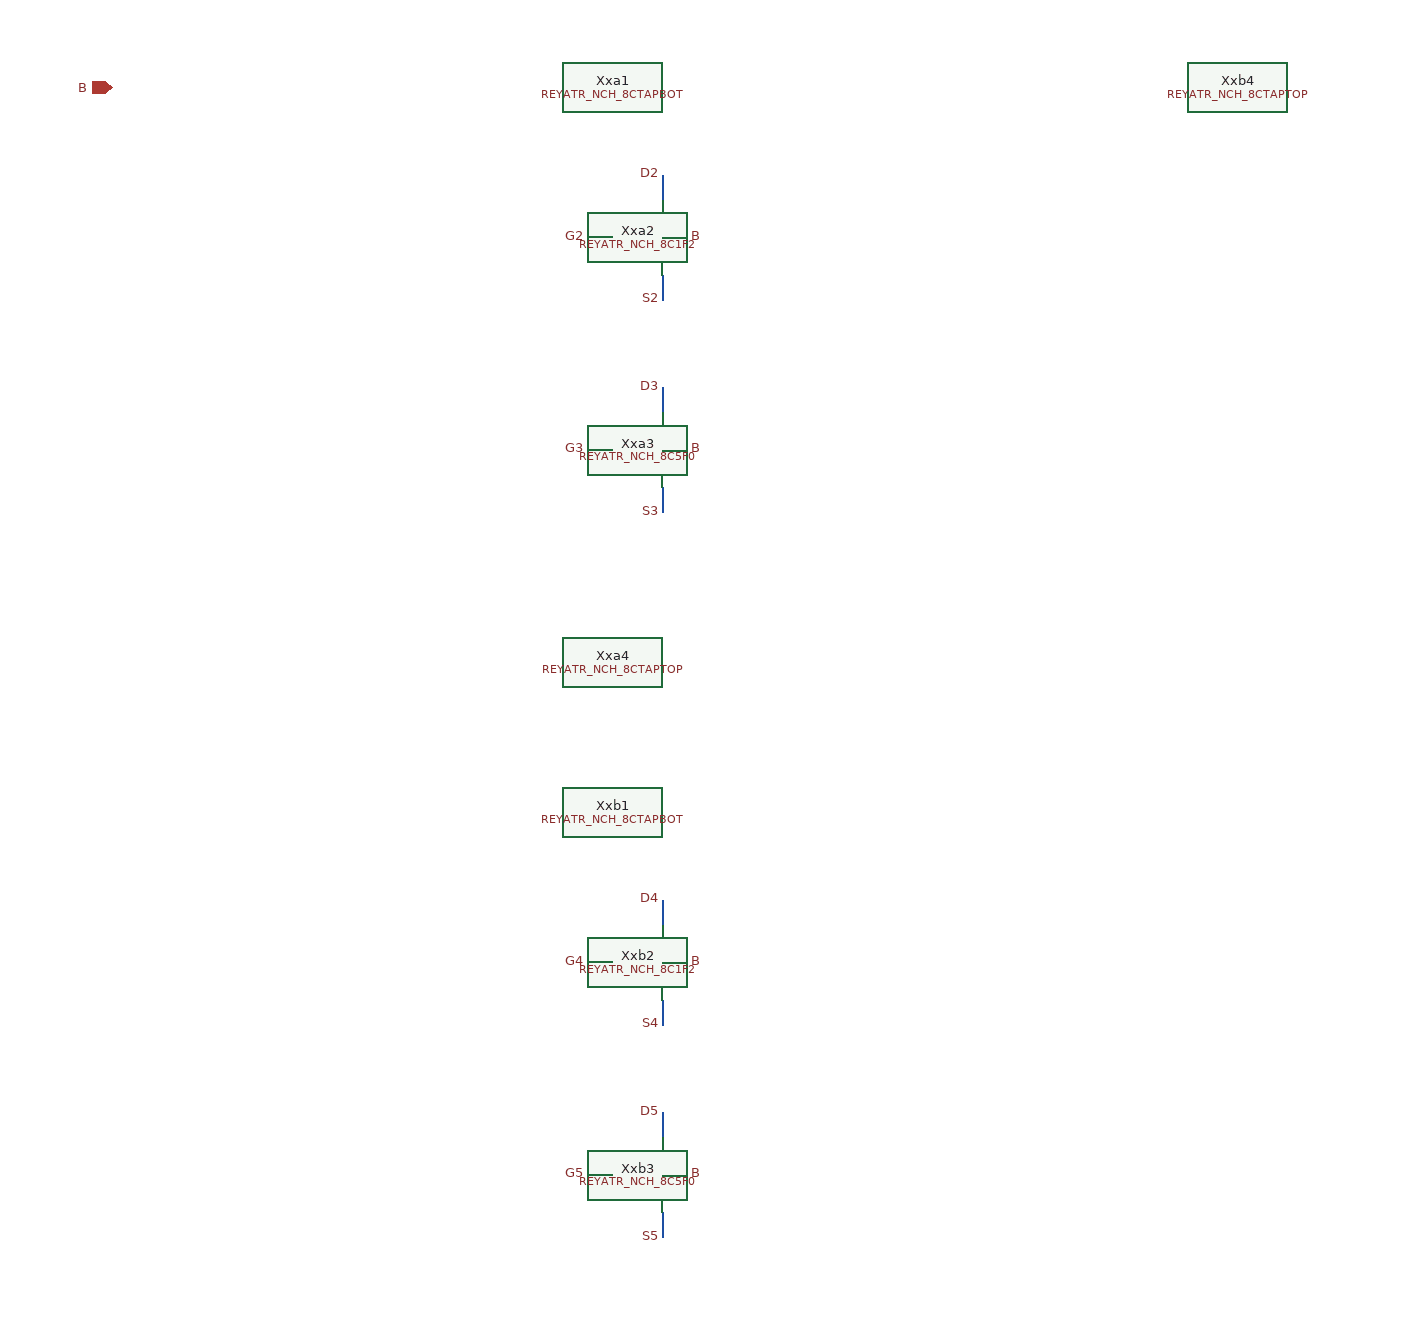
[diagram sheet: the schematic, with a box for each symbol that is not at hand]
v {xschem version=3.0.0 file_version=1.2 }
G {}
K {}
V {}
S {}
E {}
C {devices/iopin.sym} 0 0 0 0 {name=p0 lab=B}
C {LELO_TEMP_SKY130A/REYATR_NCH_8CTAPBOT.sym} 400 0 0 0 {name=Xxa1}
C {LELO_TEMP_SKY130A/REYATR_NCH_8C1F2.sym} 400 120.0 0 0 {name=Xxa2}
N 440.0 70.0 440.0 90.0 {lab=D2}
C {devices/lab_pin.sym} 440.0 70.0 3 0 {name=l0 sig_type=std_logic lab=D2 }
N 380.0 120.0 400.0 120.0 {lab=G2}
C {devices/lab_pin.sym} 380.0 120.0 0 0 {name=l1 sig_type=std_logic lab=G2 }
N 440.0 170.0 440.0 150.0 {lab=S2}
C {devices/lab_pin.sym} 440.0 170.0 1 0 {name=l2 sig_type=std_logic lab=S2 }
N 460.0 120.0 440.0 120.0 {lab=B}
C {devices/lab_pin.sym} 460.0 120.0 2 0 {name=l3 sig_type=std_logic lab=B }
C {LELO_TEMP_SKY130A/REYATR_NCH_8C5F0.sym} 400 290.0 0 0 {name=Xxa3}
N 440.0 240.0 440.0 260.0 {lab=D3}
C {devices/lab_pin.sym} 440.0 240.0 3 0 {name=l4 sig_type=std_logic lab=D3 }
N 380.0 290.0 400.0 290.0 {lab=G3}
C {devices/lab_pin.sym} 380.0 290.0 0 0 {name=l5 sig_type=std_logic lab=G3 }
N 440.0 340.0 440.0 320.0 {lab=S3}
C {devices/lab_pin.sym} 440.0 340.0 1 0 {name=l6 sig_type=std_logic lab=S3 }
N 460.0 290.0 440.0 290.0 {lab=B}
C {devices/lab_pin.sym} 460.0 290.0 2 0 {name=l7 sig_type=std_logic lab=B }
C {LELO_TEMP_SKY130A/REYATR_NCH_8CTAPTOP.sym} 400 460.0 0 0 {name=Xxa4}
C {LELO_TEMP_SKY130A/REYATR_NCH_8CTAPBOT.sym} 400 580.0 0 0 {name=Xxb1}
C {LELO_TEMP_SKY130A/REYATR_NCH_8C1F2.sym} 400 700.0 0 0 {name=Xxb2}
N 440.0 650.0 440.0 670.0 {lab=D4}
C {devices/lab_pin.sym} 440.0 650.0 3 0 {name=l8 sig_type=std_logic lab=D4 }
N 380.0 700.0 400.0 700.0 {lab=G4}
C {devices/lab_pin.sym} 380.0 700.0 0 0 {name=l9 sig_type=std_logic lab=G4 }
N 440.0 750.0 440.0 730.0 {lab=S4}
C {devices/lab_pin.sym} 440.0 750.0 1 0 {name=l10 sig_type=std_logic lab=S4 }
N 460.0 700.0 440.0 700.0 {lab=B}
C {devices/lab_pin.sym} 460.0 700.0 2 0 {name=l11 sig_type=std_logic lab=B }
C {LELO_TEMP_SKY130A/REYATR_NCH_8C5F0.sym} 400 870.0 0 0 {name=Xxb3}
N 440.0 820.0 440.0 840.0 {lab=D5}
C {devices/lab_pin.sym} 440.0 820.0 3 0 {name=l12 sig_type=std_logic lab=D5 }
N 380.0 870.0 400.0 870.0 {lab=G5}
C {devices/lab_pin.sym} 380.0 870.0 0 0 {name=l13 sig_type=std_logic lab=G5 }
N 440.0 920.0 440.0 900.0 {lab=S5}
C {devices/lab_pin.sym} 440.0 920.0 1 0 {name=l14 sig_type=std_logic lab=S5 }
N 460.0 870.0 440.0 870.0 {lab=B}
C {devices/lab_pin.sym} 460.0 870.0 2 0 {name=l15 sig_type=std_logic lab=B }
C {LELO_TEMP_SKY130A/REYATR_NCH_8CTAPTOP.sym} 900 0 0 0 {name=Xxb4}
